VERSION 5.7 ;
  NOWIREEXTENSIONATPIN ON ;
  DIVIDERCHAR "/" ;
  BUSBITCHARS "[]" ;
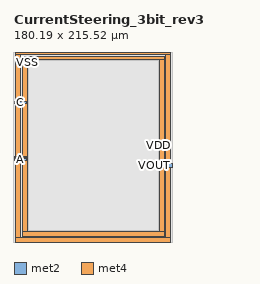
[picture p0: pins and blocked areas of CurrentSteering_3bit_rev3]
MACRO CurrentSteering_3bit_rev3
  CLASS BLOCK ;
  FOREIGN CurrentSteering_3bit_rev3 ;
  ORIGIN -36.730 137.180 ;
  SIZE 180.190 BY 215.520 ;
  PIN A
    USE SIGNAL ;
    ANTENNAGATEAREA 400.000000 ;
    PORT
      LAYER met2 ;
        RECT 36.820 -44.680 51 -42.990 ;
    END
  END A
  PIN B
    USE SIGNAL ;
    ANTENNAGATEAREA 800.000000 ;
    PORT
      LAYER met2 ;
        RECT 36.820 -41.470 51 -39.780 ;
    END
  END B
  PIN C
    USE SIGNAL ;
    ANTENNAGATEAREA 1600.000000 ;
    PORT
      LAYER met2 ;
        RECT 36.730 19.740 51 22.090 ;
    END
  END C
  PIN VOUT
    USE SIGNAL ;
    ANTENNADIFFAREA 974.399963 ;
    PORT
      LAYER met2 ;
        RECT 201 -52.320 216.920 -48.480 ;
    END
  END VOUT
  PIN VDD
    USE POWER ;
    ANTENNADIFFAREA 106.574997 ;
    PORT
      LAYER met4 ;
        RECT 46.210 69.710 207.460 73.770 ;
        RECT 46.210 -125.470 51.900 69.710 ;
        RECT 201.240 -125.470 207.460 69.710 ;
        RECT 46.210 -130.890 207.460 -125.470 ;
    END
  END VDD
  PIN VSS
    USE GROUND ;
    ANTENNADIFFAREA 33.846699 ;
    PORT
      LAYER met4 ;
        RECT 38.770 75.200 214.730 78.340 ;
        RECT 38.770 -132.380 44.620 75.200 ;
        RECT 208.880 -132.380 214.730 75.200 ;
        RECT 38.770 -137.180 214.730 -132.380 ;
    END
  END VSS
  OBS
      LAYER pwell ;
        RECT 53 -124 201 69 ;
        RECT 36.19 -137.52 216 78 ;

        RECT 85.340 16.310 95.230 58.890 ;
        RECT 103.570 16.150 113.460 58.730 ;
        RECT 121.970 16.100 131.860 58.680 ;
        RECT 140.740 16.250 150.630 58.830 ;
        RECT 59.530 -47.920 69.420 -5.340 ;
        RECT 76.580 -47.920 86.470 -5.340 ;
        RECT 102.420 -47.940 112.310 -5.360 ;
        RECT 123.440 -47.940 133.330 -5.360 ;
        RECT 147.510 -47.970 157.400 -5.390 ;
        RECT 165.580 -47.970 175.470 -5.390 ;
        RECT 88.620 -115.630 98.510 -73.050 ;
        RECT 105.010 -115.630 114.900 -73.050 ;
        RECT 120.970 -115.630 130.860 -73.050 ;
        RECT 137.960 -115.630 147.850 -73.050 ;
      LAYER li1 ;
        RECT 53 -124 201 69 ;
        RECT 36.19 -137.52 216 78 ;

        RECT 62.245 60.815 62.415 62.815 ;
        RECT 72.885 60.815 73.055 62.815 ;
        RECT 87.580 62.010 87.750 62.510 ;
        RECT 93.220 62.010 93.390 62.510 ;
        RECT 87.965 61.780 93.005 61.950 ;
        RECT 105.810 61.850 105.980 62.350 ;
        RECT 111.450 61.850 111.620 62.350 ;
        RECT 124.210 61.800 124.380 62.300 ;
        RECT 129.850 61.800 130.020 62.300 ;
        RECT 142.980 61.950 143.150 62.450 ;
        RECT 148.620 61.950 148.790 62.450 ;
        RECT 106.195 61.620 111.235 61.790 ;
        RECT 124.595 61.570 129.635 61.740 ;
        RECT 143.365 61.720 148.405 61.890 ;
        RECT 62.630 60.585 72.670 60.755 ;
        RECT 85.580 58.480 94.990 58.650 ;
        RECT 64.730 54.890 70.460 57.050 ;
        RECT 85.580 16.720 85.750 58.480 ;
        RECT 87.040 17.580 87.210 57.620 ;
        RECT 88.620 17.580 88.790 57.620 ;
        RECT 90.200 17.580 90.370 57.620 ;
        RECT 91.780 17.580 91.950 57.620 ;
        RECT 93.360 17.580 93.530 57.620 ;
        RECT 94.820 16.720 94.990 58.480 ;
        RECT 85.580 16.550 94.990 16.720 ;
        RECT 103.810 58.320 113.220 58.490 ;
        RECT 103.810 16.560 103.980 58.320 ;
        RECT 105.270 17.420 105.440 57.460 ;
        RECT 106.850 17.420 107.020 57.460 ;
        RECT 108.430 17.420 108.600 57.460 ;
        RECT 110.010 17.420 110.180 57.460 ;
        RECT 111.590 17.420 111.760 57.460 ;
        RECT 113.050 16.560 113.220 58.320 ;
        RECT 103.810 16.390 113.220 16.560 ;
        RECT 122.210 58.270 131.620 58.440 ;
        RECT 122.210 16.510 122.380 58.270 ;
        RECT 123.670 17.370 123.840 57.410 ;
        RECT 125.250 17.370 125.420 57.410 ;
        RECT 126.830 17.370 127.000 57.410 ;
        RECT 128.410 17.370 128.580 57.410 ;
        RECT 129.990 17.370 130.160 57.410 ;
        RECT 131.450 16.510 131.620 58.270 ;
        RECT 122.210 16.340 131.620 16.510 ;
        RECT 140.980 58.420 150.390 58.590 ;
        RECT 140.980 16.660 141.150 58.420 ;
        RECT 142.440 17.520 142.610 57.560 ;
        RECT 144.020 17.520 144.190 57.560 ;
        RECT 145.600 17.520 145.770 57.560 ;
        RECT 147.180 17.520 147.350 57.560 ;
        RECT 148.760 17.520 148.930 57.560 ;
        RECT 150.220 16.660 150.390 58.420 ;
        RECT 140.980 16.490 150.390 16.660 ;
        RECT 178.060 6.990 182.050 31.190 ;
        RECT 61.770 -2.220 61.940 -1.720 ;
        RECT 67.410 -2.220 67.580 -1.720 ;
        RECT 78.820 -2.220 78.990 -1.720 ;
        RECT 84.460 -2.220 84.630 -1.720 ;
        RECT 104.660 -2.240 104.830 -1.740 ;
        RECT 110.300 -2.240 110.470 -1.740 ;
        RECT 125.680 -2.240 125.850 -1.740 ;
        RECT 131.320 -2.240 131.490 -1.740 ;
        RECT 149.750 -2.270 149.920 -1.770 ;
        RECT 155.390 -2.270 155.560 -1.770 ;
        RECT 167.820 -2.270 167.990 -1.770 ;
        RECT 173.460 -2.270 173.630 -1.770 ;
        RECT 62.155 -2.450 67.195 -2.280 ;
        RECT 79.205 -2.450 84.245 -2.280 ;
        RECT 105.045 -2.470 110.085 -2.300 ;
        RECT 126.065 -2.470 131.105 -2.300 ;
        RECT 150.135 -2.500 155.175 -2.330 ;
        RECT 168.205 -2.500 173.245 -2.330 ;
        RECT 59.770 -5.750 69.180 -5.580 ;
        RECT 59.770 -47.510 59.940 -5.750 ;
        RECT 61.230 -46.650 61.400 -6.610 ;
        RECT 62.810 -46.650 62.980 -6.610 ;
        RECT 64.390 -46.650 64.560 -6.610 ;
        RECT 65.970 -46.650 66.140 -6.610 ;
        RECT 67.550 -46.650 67.720 -6.610 ;
        RECT 69.010 -47.510 69.180 -5.750 ;
        RECT 59.770 -47.680 69.180 -47.510 ;
        RECT 76.820 -5.750 86.230 -5.580 ;
        RECT 76.820 -47.510 76.990 -5.750 ;
        RECT 78.280 -46.650 78.450 -6.610 ;
        RECT 79.860 -46.650 80.030 -6.610 ;
        RECT 81.440 -46.650 81.610 -6.610 ;
        RECT 83.020 -46.650 83.190 -6.610 ;
        RECT 84.600 -46.650 84.770 -6.610 ;
        RECT 86.060 -47.510 86.230 -5.750 ;
        RECT 76.820 -47.680 86.230 -47.510 ;
        RECT 102.660 -5.770 112.070 -5.600 ;
        RECT 102.660 -47.530 102.830 -5.770 ;
        RECT 104.120 -46.670 104.290 -6.630 ;
        RECT 105.700 -46.670 105.870 -6.630 ;
        RECT 107.280 -46.670 107.450 -6.630 ;
        RECT 108.860 -46.670 109.030 -6.630 ;
        RECT 110.440 -46.670 110.610 -6.630 ;
        RECT 111.900 -47.530 112.070 -5.770 ;
        RECT 102.660 -47.700 112.070 -47.530 ;
        RECT 123.680 -5.770 133.090 -5.600 ;
        RECT 123.680 -47.530 123.850 -5.770 ;
        RECT 125.140 -46.670 125.310 -6.630 ;
        RECT 126.720 -46.670 126.890 -6.630 ;
        RECT 128.300 -46.670 128.470 -6.630 ;
        RECT 129.880 -46.670 130.050 -6.630 ;
        RECT 131.460 -46.670 131.630 -6.630 ;
        RECT 132.920 -47.530 133.090 -5.770 ;
        RECT 123.680 -47.700 133.090 -47.530 ;
        RECT 147.750 -5.800 157.160 -5.630 ;
        RECT 147.750 -47.560 147.920 -5.800 ;
        RECT 149.210 -46.700 149.380 -6.660 ;
        RECT 150.790 -46.700 150.960 -6.660 ;
        RECT 152.370 -46.700 152.540 -6.660 ;
        RECT 153.950 -46.700 154.120 -6.660 ;
        RECT 155.530 -46.700 155.700 -6.660 ;
        RECT 156.990 -47.560 157.160 -5.800 ;
        RECT 147.750 -47.730 157.160 -47.560 ;
        RECT 165.820 -5.800 175.230 -5.630 ;
        RECT 165.820 -47.560 165.990 -5.800 ;
        RECT 167.280 -46.700 167.450 -6.660 ;
        RECT 168.860 -46.700 169.030 -6.660 ;
        RECT 170.440 -46.700 170.610 -6.660 ;
        RECT 172.020 -46.700 172.190 -6.660 ;
        RECT 173.600 -46.700 173.770 -6.660 ;
        RECT 175.060 -47.560 175.230 -5.800 ;
        RECT 165.820 -47.730 175.230 -47.560 ;
        RECT 178.070 -57.480 182.020 -43.300 ;
        RECT 90.860 -69.930 91.030 -69.430 ;
        RECT 96.500 -69.930 96.670 -69.430 ;
        RECT 107.250 -69.930 107.420 -69.430 ;
        RECT 112.890 -69.930 113.060 -69.430 ;
        RECT 123.210 -69.930 123.380 -69.430 ;
        RECT 128.850 -69.930 129.020 -69.430 ;
        RECT 140.200 -69.930 140.370 -69.430 ;
        RECT 145.840 -69.930 146.010 -69.430 ;
        RECT 91.245 -70.160 96.285 -69.990 ;
        RECT 107.635 -70.160 112.675 -69.990 ;
        RECT 123.595 -70.160 128.635 -69.990 ;
        RECT 140.585 -70.160 145.625 -69.990 ;
        RECT 88.860 -73.460 98.270 -73.290 ;
        RECT 88.860 -115.220 89.030 -73.460 ;
        RECT 90.320 -114.360 90.490 -74.320 ;
        RECT 91.900 -114.360 92.070 -74.320 ;
        RECT 93.480 -114.360 93.650 -74.320 ;
        RECT 95.060 -114.360 95.230 -74.320 ;
        RECT 96.640 -114.360 96.810 -74.320 ;
        RECT 98.100 -115.220 98.270 -73.460 ;
        RECT 88.860 -115.390 98.270 -115.220 ;
        RECT 105.250 -73.460 114.660 -73.290 ;
        RECT 105.250 -115.220 105.420 -73.460 ;
        RECT 106.710 -114.360 106.880 -74.320 ;
        RECT 108.290 -114.360 108.460 -74.320 ;
        RECT 109.870 -114.360 110.040 -74.320 ;
        RECT 111.450 -114.360 111.620 -74.320 ;
        RECT 113.030 -114.360 113.200 -74.320 ;
        RECT 114.490 -115.220 114.660 -73.460 ;
        RECT 105.250 -115.390 114.660 -115.220 ;
        RECT 121.210 -73.460 130.620 -73.290 ;
        RECT 121.210 -115.220 121.380 -73.460 ;
        RECT 122.670 -114.360 122.840 -74.320 ;
        RECT 124.250 -114.360 124.420 -74.320 ;
        RECT 125.830 -114.360 126.000 -74.320 ;
        RECT 127.410 -114.360 127.580 -74.320 ;
        RECT 128.990 -114.360 129.160 -74.320 ;
        RECT 130.450 -115.220 130.620 -73.460 ;
        RECT 121.210 -115.390 130.620 -115.220 ;
        RECT 138.200 -73.460 147.610 -73.290 ;
        RECT 138.200 -115.220 138.370 -73.460 ;
        RECT 139.660 -114.360 139.830 -74.320 ;
        RECT 141.240 -114.360 141.410 -74.320 ;
        RECT 142.820 -114.360 142.990 -74.320 ;
        RECT 144.400 -114.360 144.570 -74.320 ;
        RECT 145.980 -114.360 146.150 -74.320 ;
        RECT 147.440 -115.220 147.610 -73.460 ;
        RECT 138.200 -115.390 147.610 -115.220 ;
      LAYER mcon ;
        RECT 53 -124 201 69 ;
        RECT 36.19 -137.52 216 78 ;

        RECT 62.245 60.895 62.415 62.735 ;
        RECT 72.885 60.895 73.055 62.735 ;
        RECT 87.580 62.090 87.750 62.430 ;
        RECT 93.220 62.090 93.390 62.430 ;
        RECT 88.045 61.780 92.925 61.950 ;
        RECT 105.810 61.930 105.980 62.270 ;
        RECT 111.450 61.930 111.620 62.270 ;
        RECT 124.210 61.880 124.380 62.220 ;
        RECT 129.850 61.880 130.020 62.220 ;
        RECT 142.980 62.030 143.150 62.370 ;
        RECT 148.620 62.030 148.790 62.370 ;
        RECT 106.275 61.620 111.155 61.790 ;
        RECT 124.675 61.570 129.555 61.740 ;
        RECT 143.445 61.720 148.325 61.890 ;
        RECT 62.710 60.585 72.590 60.755 ;
        RECT 64.810 54.975 70.380 56.960 ;
        RECT 87.040 17.660 87.210 57.540 ;
        RECT 88.620 17.660 88.790 57.540 ;
        RECT 90.200 17.660 90.370 57.540 ;
        RECT 91.780 17.660 91.950 57.540 ;
        RECT 93.360 17.660 93.530 57.540 ;
        RECT 105.270 17.500 105.440 57.380 ;
        RECT 106.850 17.500 107.020 57.380 ;
        RECT 108.430 17.500 108.600 57.380 ;
        RECT 110.010 17.500 110.180 57.380 ;
        RECT 111.590 17.500 111.760 57.380 ;
        RECT 123.670 17.450 123.840 57.330 ;
        RECT 125.250 17.450 125.420 57.330 ;
        RECT 126.830 17.450 127.000 57.330 ;
        RECT 128.410 17.450 128.580 57.330 ;
        RECT 129.990 17.450 130.160 57.330 ;
        RECT 142.440 17.600 142.610 57.480 ;
        RECT 144.020 17.600 144.190 57.480 ;
        RECT 145.600 17.600 145.770 57.480 ;
        RECT 147.180 17.600 147.350 57.480 ;
        RECT 148.760 17.600 148.930 57.480 ;
        RECT 178.250 29.440 179.870 30.110 ;
        RECT 180.290 29.390 181.910 30.060 ;
        RECT 178.230 28.400 179.850 29.070 ;
        RECT 180.270 28.440 181.890 29.110 ;
        RECT 178.230 27.530 179.850 28.200 ;
        RECT 180.260 27.530 181.880 28.200 ;
        RECT 178.220 26.610 179.840 27.280 ;
        RECT 180.260 26.630 181.880 27.300 ;
        RECT 178.280 17.820 179.330 18.570 ;
        RECT 180.530 17.870 181.580 18.620 ;
        RECT 178.210 9.810 179.830 10.480 ;
        RECT 180.310 9.830 181.930 10.500 ;
        RECT 178.200 8.940 179.820 9.610 ;
        RECT 180.340 8.940 181.960 9.610 ;
        RECT 178.210 8.010 179.830 8.680 ;
        RECT 180.350 8.020 181.970 8.690 ;
        RECT 61.770 -2.140 61.940 -1.800 ;
        RECT 67.410 -2.140 67.580 -1.800 ;
        RECT 78.820 -2.140 78.990 -1.800 ;
        RECT 84.460 -2.140 84.630 -1.800 ;
        RECT 104.660 -2.160 104.830 -1.820 ;
        RECT 110.300 -2.160 110.470 -1.820 ;
        RECT 125.680 -2.160 125.850 -1.820 ;
        RECT 131.320 -2.160 131.490 -1.820 ;
        RECT 149.750 -2.190 149.920 -1.850 ;
        RECT 155.390 -2.190 155.560 -1.850 ;
        RECT 167.820 -2.190 167.990 -1.850 ;
        RECT 173.460 -2.190 173.630 -1.850 ;
        RECT 62.235 -2.450 67.115 -2.280 ;
        RECT 79.285 -2.450 84.165 -2.280 ;
        RECT 105.125 -2.470 110.005 -2.300 ;
        RECT 126.145 -2.470 131.025 -2.300 ;
        RECT 150.215 -2.500 155.095 -2.330 ;
        RECT 168.285 -2.500 173.165 -2.330 ;
        RECT 61.230 -46.570 61.400 -6.690 ;
        RECT 62.810 -46.570 62.980 -6.690 ;
        RECT 64.390 -46.570 64.560 -6.690 ;
        RECT 65.970 -46.570 66.140 -6.690 ;
        RECT 67.550 -46.570 67.720 -6.690 ;
        RECT 78.280 -46.570 78.450 -6.690 ;
        RECT 79.860 -46.570 80.030 -6.690 ;
        RECT 81.440 -46.570 81.610 -6.690 ;
        RECT 83.020 -46.570 83.190 -6.690 ;
        RECT 84.600 -46.570 84.770 -6.690 ;
        RECT 104.120 -46.590 104.290 -6.710 ;
        RECT 105.700 -46.590 105.870 -6.710 ;
        RECT 107.280 -46.590 107.450 -6.710 ;
        RECT 108.860 -46.590 109.030 -6.710 ;
        RECT 110.440 -46.590 110.610 -6.710 ;
        RECT 125.140 -46.590 125.310 -6.710 ;
        RECT 126.720 -46.590 126.890 -6.710 ;
        RECT 128.300 -46.590 128.470 -6.710 ;
        RECT 129.880 -46.590 130.050 -6.710 ;
        RECT 131.460 -46.590 131.630 -6.710 ;
        RECT 149.210 -46.620 149.380 -6.740 ;
        RECT 150.790 -46.620 150.960 -6.740 ;
        RECT 152.370 -46.620 152.540 -6.740 ;
        RECT 153.950 -46.620 154.120 -6.740 ;
        RECT 155.530 -46.620 155.700 -6.740 ;
        RECT 167.280 -46.620 167.450 -6.740 ;
        RECT 168.860 -46.620 169.030 -6.740 ;
        RECT 170.440 -46.620 170.610 -6.740 ;
        RECT 172.020 -46.620 172.190 -6.740 ;
        RECT 173.600 -46.620 173.770 -6.740 ;
        RECT 178.560 -44.520 179.450 -43.780 ;
        RECT 180.460 -44.540 181.350 -43.800 ;
        RECT 178.520 -46.010 179.410 -45.270 ;
        RECT 180.450 -46.000 181.340 -45.260 ;
        RECT 178.470 -54.760 179.360 -54.020 ;
        RECT 180.670 -54.720 181.560 -53.980 ;
        RECT 178.420 -57.190 179.310 -56.450 ;
        RECT 180.670 -57.170 181.560 -56.430 ;
        RECT 90.860 -69.850 91.030 -69.510 ;
        RECT 96.500 -69.850 96.670 -69.510 ;
        RECT 107.250 -69.850 107.420 -69.510 ;
        RECT 112.890 -69.850 113.060 -69.510 ;
        RECT 123.210 -69.850 123.380 -69.510 ;
        RECT 128.850 -69.850 129.020 -69.510 ;
        RECT 140.200 -69.850 140.370 -69.510 ;
        RECT 145.840 -69.850 146.010 -69.510 ;
        RECT 91.325 -70.160 96.205 -69.990 ;
        RECT 107.715 -70.160 112.595 -69.990 ;
        RECT 123.675 -70.160 128.555 -69.990 ;
        RECT 140.665 -70.160 145.545 -69.990 ;
        RECT 90.320 -114.280 90.490 -74.400 ;
        RECT 91.900 -114.280 92.070 -74.400 ;
        RECT 93.480 -114.280 93.650 -74.400 ;
        RECT 95.060 -114.280 95.230 -74.400 ;
        RECT 96.640 -114.280 96.810 -74.400 ;
        RECT 106.710 -114.280 106.880 -74.400 ;
        RECT 108.290 -114.280 108.460 -74.400 ;
        RECT 109.870 -114.280 110.040 -74.400 ;
        RECT 111.450 -114.280 111.620 -74.400 ;
        RECT 113.030 -114.280 113.200 -74.400 ;
        RECT 122.670 -114.280 122.840 -74.400 ;
        RECT 124.250 -114.280 124.420 -74.400 ;
        RECT 125.830 -114.280 126.000 -74.400 ;
        RECT 127.410 -114.280 127.580 -74.400 ;
        RECT 128.990 -114.280 129.160 -74.400 ;
        RECT 139.660 -114.280 139.830 -74.400 ;
        RECT 141.240 -114.280 141.410 -74.400 ;
        RECT 142.820 -114.280 142.990 -74.400 ;
        RECT 144.400 -114.280 144.570 -74.400 ;
        RECT 145.980 -114.280 146.150 -74.400 ;
      LAYER met1 ;
        RECT 53 -124 201 69 ;
        RECT 36.19 -137.52 216 78 ;

        RECT 82.560 62.820 86.190 62.900 ;
        RECT 77.710 62.810 86.190 62.820 ;
        RECT 62.215 62.180 62.445 62.795 ;
        RECT 72.810 62.490 86.190 62.810 ;
        RECT 72.810 62.180 87.790 62.490 ;
        RECT 62.215 62.030 87.790 62.180 ;
        RECT 93.190 62.030 93.420 62.490 ;
        RECT 100.790 62.330 104.420 62.740 ;
        RECT 62.215 61.580 86.190 62.030 ;
        RECT 88.190 61.980 92.680 62.010 ;
        RECT 87.985 61.750 92.985 61.980 ;
        RECT 100.790 61.870 106.020 62.330 ;
        RECT 111.420 61.870 111.650 62.330 ;
        RECT 119.190 62.280 122.820 62.690 ;
        RECT 137.960 62.430 141.590 62.840 ;
        RECT 62.215 61.490 84.150 61.580 ;
        RECT 62.215 60.835 62.445 61.490 ;
        RECT 72.810 60.820 84.150 61.490 ;
        RECT 75.050 60.810 84.150 60.820 ;
        RECT 63.080 60.785 72.100 60.790 ;
        RECT 62.650 60.555 72.650 60.785 ;
        RECT 63.080 60.350 72.100 60.555 ;
        RECT 64.730 59.860 72.100 60.350 ;
        RECT 64.730 59.690 72.120 59.860 ;
        RECT 75.050 59.690 83.190 60.810 ;
        RECT 64.730 57.970 83.190 59.690 ;
        RECT 88.190 59.340 92.680 61.750 ;
        RECT 100.790 61.420 104.420 61.870 ;
        RECT 106.420 61.820 110.910 61.850 ;
        RECT 119.190 61.820 124.420 62.280 ;
        RECT 129.820 61.820 130.050 62.280 ;
        RECT 137.960 61.970 143.190 62.430 ;
        RECT 148.590 61.970 148.820 62.430 ;
        RECT 106.215 61.590 111.215 61.820 ;
        RECT 64.730 56.520 70.480 57.970 ;
        RECT 64.750 54.945 70.440 56.520 ;
        RECT 77.840 53.390 83.190 57.970 ;
        RECT 87.010 57.130 87.240 57.600 ;
        RECT 86.900 56.530 87.330 57.130 ;
        RECT 88.590 57.090 88.820 57.600 ;
        RECT 90.170 57.090 90.400 57.600 ;
        RECT 88.530 56.590 88.960 57.090 ;
        RECT 90.050 56.590 90.480 57.090 ;
        RECT 91.750 57.080 91.980 57.600 ;
        RECT 93.330 57.080 93.560 57.600 ;
        RECT 87.010 17.600 87.240 56.530 ;
        RECT 88.590 17.600 88.820 56.590 ;
        RECT 90.170 17.600 90.400 56.590 ;
        RECT 91.640 56.580 92.070 57.080 ;
        RECT 93.180 56.580 93.610 57.080 ;
        RECT 91.750 17.600 91.980 56.580 ;
        RECT 93.330 17.600 93.560 56.580 ;
        RECT 100.810 54.170 102.610 61.420 ;
        RECT 106.420 59.180 110.910 61.590 ;
        RECT 119.190 61.370 122.820 61.820 ;
        RECT 124.820 61.770 129.310 61.800 ;
        RECT 124.615 61.540 129.615 61.770 ;
        RECT 105.240 56.970 105.470 57.440 ;
        RECT 105.130 56.370 105.560 56.970 ;
        RECT 106.820 56.930 107.050 57.440 ;
        RECT 108.400 56.930 108.630 57.440 ;
        RECT 106.760 56.430 107.190 56.930 ;
        RECT 108.280 56.430 108.710 56.930 ;
        RECT 109.980 56.920 110.210 57.440 ;
        RECT 111.560 56.920 111.790 57.440 ;
        RECT 105.240 17.440 105.470 56.370 ;
        RECT 106.820 17.440 107.050 56.430 ;
        RECT 108.400 17.440 108.630 56.430 ;
        RECT 109.870 56.420 110.300 56.920 ;
        RECT 111.410 56.420 111.840 56.920 ;
        RECT 109.980 17.440 110.210 56.420 ;
        RECT 111.560 17.440 111.790 56.420 ;
        RECT 119.220 54.100 121.330 61.370 ;
        RECT 124.820 59.130 129.310 61.540 ;
        RECT 137.960 61.520 141.590 61.970 ;
        RECT 143.590 61.920 148.080 61.950 ;
        RECT 143.385 61.690 148.385 61.920 ;
        RECT 123.640 56.920 123.870 57.390 ;
        RECT 123.530 56.320 123.960 56.920 ;
        RECT 125.220 56.880 125.450 57.390 ;
        RECT 126.800 56.880 127.030 57.390 ;
        RECT 125.160 56.380 125.590 56.880 ;
        RECT 126.680 56.380 127.110 56.880 ;
        RECT 128.380 56.870 128.610 57.390 ;
        RECT 129.960 56.870 130.190 57.390 ;
        RECT 123.640 17.390 123.870 56.320 ;
        RECT 125.220 17.390 125.450 56.380 ;
        RECT 126.800 17.390 127.030 56.380 ;
        RECT 128.270 56.370 128.700 56.870 ;
        RECT 129.810 56.370 130.240 56.870 ;
        RECT 128.380 17.390 128.610 56.370 ;
        RECT 129.960 17.390 130.190 56.370 ;
        RECT 138.030 54.190 140.140 61.520 ;
        RECT 143.590 59.280 148.080 61.690 ;
        RECT 142.410 57.070 142.640 57.540 ;
        RECT 142.300 56.470 142.730 57.070 ;
        RECT 143.990 57.030 144.220 57.540 ;
        RECT 145.570 57.030 145.800 57.540 ;
        RECT 143.930 56.530 144.360 57.030 ;
        RECT 145.450 56.530 145.880 57.030 ;
        RECT 147.150 57.020 147.380 57.540 ;
        RECT 148.730 57.020 148.960 57.540 ;
        RECT 142.410 17.540 142.640 56.470 ;
        RECT 143.990 17.540 144.220 56.530 ;
        RECT 145.570 17.540 145.800 56.530 ;
        RECT 147.040 56.520 147.470 57.020 ;
        RECT 148.580 56.520 149.010 57.020 ;
        RECT 147.150 17.540 147.380 56.520 ;
        RECT 148.730 17.540 148.960 56.520 ;
        RECT 178.060 17.220 182.050 31.190 ;
        RECT 178.060 6.990 182.050 10.620 ;
        RECT 56.750 -1.740 60.380 -1.330 ;
        RECT 73.800 -1.740 77.430 -1.330 ;
        RECT 56.750 -2.200 61.980 -1.740 ;
        RECT 67.380 -2.200 67.610 -1.740 ;
        RECT 73.800 -2.200 79.030 -1.740 ;
        RECT 84.430 -2.200 84.660 -1.740 ;
        RECT 99.640 -1.760 103.270 -1.350 ;
        RECT 120.660 -1.760 124.290 -1.350 ;
        RECT 56.750 -2.650 60.380 -2.200 ;
        RECT 62.380 -2.250 66.870 -2.220 ;
        RECT 62.175 -2.480 67.175 -2.250 ;
        RECT 56.920 -11.860 58.960 -2.650 ;
        RECT 62.380 -4.890 66.870 -2.480 ;
        RECT 73.800 -2.650 77.430 -2.200 ;
        RECT 99.640 -2.220 104.870 -1.760 ;
        RECT 110.270 -2.220 110.500 -1.760 ;
        RECT 120.660 -2.220 125.890 -1.760 ;
        RECT 131.290 -2.220 131.520 -1.760 ;
        RECT 144.730 -1.790 148.360 -1.380 ;
        RECT 162.800 -1.790 166.430 -1.380 ;
        RECT 79.430 -2.250 83.920 -2.220 ;
        RECT 79.225 -2.480 84.225 -2.250 ;
        RECT 61.200 -7.100 61.430 -6.630 ;
        RECT 61.090 -7.700 61.520 -7.100 ;
        RECT 62.780 -7.140 63.010 -6.630 ;
        RECT 64.360 -7.140 64.590 -6.630 ;
        RECT 62.720 -7.640 63.150 -7.140 ;
        RECT 64.240 -7.640 64.670 -7.140 ;
        RECT 65.940 -7.150 66.170 -6.630 ;
        RECT 67.520 -7.150 67.750 -6.630 ;
        RECT 61.200 -46.630 61.430 -7.700 ;
        RECT 62.780 -46.630 63.010 -7.640 ;
        RECT 64.360 -46.630 64.590 -7.640 ;
        RECT 65.830 -7.650 66.260 -7.150 ;
        RECT 67.370 -7.650 67.800 -7.150 ;
        RECT 65.940 -46.630 66.170 -7.650 ;
        RECT 67.520 -46.630 67.750 -7.650 ;
        RECT 73.890 -11.940 75.930 -2.650 ;
        RECT 79.430 -4.890 83.920 -2.480 ;
        RECT 99.640 -2.670 103.270 -2.220 ;
        RECT 105.270 -2.270 109.760 -2.240 ;
        RECT 105.065 -2.500 110.065 -2.270 ;
        RECT 78.250 -7.100 78.480 -6.630 ;
        RECT 78.140 -7.700 78.570 -7.100 ;
        RECT 79.830 -7.140 80.060 -6.630 ;
        RECT 81.410 -7.140 81.640 -6.630 ;
        RECT 79.770 -7.640 80.200 -7.140 ;
        RECT 81.290 -7.640 81.720 -7.140 ;
        RECT 82.990 -7.150 83.220 -6.630 ;
        RECT 84.570 -7.150 84.800 -6.630 ;
        RECT 78.250 -46.630 78.480 -7.700 ;
        RECT 79.830 -46.630 80.060 -7.640 ;
        RECT 81.410 -46.630 81.640 -7.640 ;
        RECT 82.880 -7.650 83.310 -7.150 ;
        RECT 84.420 -7.650 84.850 -7.150 ;
        RECT 82.990 -46.630 83.220 -7.650 ;
        RECT 84.570 -46.630 84.800 -7.650 ;
        RECT 99.660 -11.900 101.700 -2.670 ;
        RECT 105.270 -4.910 109.760 -2.500 ;
        RECT 120.660 -2.670 124.290 -2.220 ;
        RECT 126.290 -2.270 130.780 -2.240 ;
        RECT 144.730 -2.250 149.960 -1.790 ;
        RECT 155.360 -2.250 155.590 -1.790 ;
        RECT 162.800 -2.250 168.030 -1.790 ;
        RECT 173.430 -2.250 173.660 -1.790 ;
        RECT 126.085 -2.500 131.085 -2.270 ;
        RECT 104.090 -7.120 104.320 -6.650 ;
        RECT 103.980 -7.720 104.410 -7.120 ;
        RECT 105.670 -7.160 105.900 -6.650 ;
        RECT 107.250 -7.160 107.480 -6.650 ;
        RECT 105.610 -7.660 106.040 -7.160 ;
        RECT 107.130 -7.660 107.560 -7.160 ;
        RECT 108.830 -7.170 109.060 -6.650 ;
        RECT 110.410 -7.170 110.640 -6.650 ;
        RECT 104.090 -46.650 104.320 -7.720 ;
        RECT 105.670 -46.650 105.900 -7.660 ;
        RECT 107.250 -46.650 107.480 -7.660 ;
        RECT 108.720 -7.670 109.150 -7.170 ;
        RECT 110.260 -7.670 110.690 -7.170 ;
        RECT 108.830 -46.650 109.060 -7.670 ;
        RECT 110.410 -46.650 110.640 -7.670 ;
        RECT 120.800 -11.810 122.840 -2.670 ;
        RECT 126.290 -4.910 130.780 -2.500 ;
        RECT 144.730 -2.700 148.360 -2.250 ;
        RECT 150.360 -2.300 154.850 -2.270 ;
        RECT 150.155 -2.530 155.155 -2.300 ;
        RECT 125.110 -7.120 125.340 -6.650 ;
        RECT 125.000 -7.720 125.430 -7.120 ;
        RECT 126.690 -7.160 126.920 -6.650 ;
        RECT 128.270 -7.160 128.500 -6.650 ;
        RECT 126.630 -7.660 127.060 -7.160 ;
        RECT 128.150 -7.660 128.580 -7.160 ;
        RECT 129.850 -7.170 130.080 -6.650 ;
        RECT 131.430 -7.170 131.660 -6.650 ;
        RECT 125.110 -46.650 125.340 -7.720 ;
        RECT 126.690 -46.650 126.920 -7.660 ;
        RECT 128.270 -46.650 128.500 -7.660 ;
        RECT 129.740 -7.670 130.170 -7.170 ;
        RECT 131.280 -7.670 131.710 -7.170 ;
        RECT 129.850 -46.650 130.080 -7.670 ;
        RECT 131.430 -46.650 131.660 -7.670 ;
        RECT 144.760 -11.880 146.800 -2.700 ;
        RECT 150.360 -4.940 154.850 -2.530 ;
        RECT 162.800 -2.700 166.430 -2.250 ;
        RECT 168.430 -2.300 172.920 -2.270 ;
        RECT 168.225 -2.530 173.225 -2.300 ;
        RECT 149.180 -7.150 149.410 -6.680 ;
        RECT 149.070 -7.750 149.500 -7.150 ;
        RECT 150.760 -7.190 150.990 -6.680 ;
        RECT 152.340 -7.190 152.570 -6.680 ;
        RECT 150.700 -7.690 151.130 -7.190 ;
        RECT 152.220 -7.690 152.650 -7.190 ;
        RECT 153.920 -7.200 154.150 -6.680 ;
        RECT 155.500 -7.200 155.730 -6.680 ;
        RECT 149.180 -46.680 149.410 -7.750 ;
        RECT 150.760 -46.680 150.990 -7.690 ;
        RECT 152.340 -46.680 152.570 -7.690 ;
        RECT 153.810 -7.700 154.240 -7.200 ;
        RECT 155.350 -7.700 155.780 -7.200 ;
        RECT 153.920 -46.680 154.150 -7.700 ;
        RECT 155.500 -46.680 155.730 -7.700 ;
        RECT 162.890 -11.860 164.930 -2.700 ;
        RECT 168.430 -4.940 172.920 -2.530 ;
        RECT 167.250 -7.150 167.480 -6.680 ;
        RECT 167.140 -7.750 167.570 -7.150 ;
        RECT 168.830 -7.190 169.060 -6.680 ;
        RECT 170.410 -7.190 170.640 -6.680 ;
        RECT 168.770 -7.690 169.200 -7.190 ;
        RECT 170.290 -7.690 170.720 -7.190 ;
        RECT 171.990 -7.200 172.220 -6.680 ;
        RECT 173.570 -7.200 173.800 -6.680 ;
        RECT 167.250 -46.680 167.480 -7.750 ;
        RECT 168.830 -46.680 169.060 -7.690 ;
        RECT 170.410 -46.680 170.640 -7.690 ;
        RECT 171.880 -7.700 172.310 -7.200 ;
        RECT 173.420 -7.700 173.850 -7.200 ;
        RECT 171.990 -46.680 172.220 -7.700 ;
        RECT 173.570 -46.680 173.800 -7.700 ;
        RECT 178.050 -46.400 182.020 -43.350 ;
        RECT 178.070 -57.480 182.030 -53.560 ;
        RECT 135.020 -69.040 137.480 -68.840 ;
        RECT 85.840 -69.450 89.470 -69.040 ;
        RECT 102.230 -69.450 105.860 -69.040 ;
        RECT 118.190 -69.450 121.820 -69.040 ;
        RECT 135.020 -69.450 138.810 -69.040 ;
        RECT 85.840 -69.910 91.070 -69.450 ;
        RECT 96.470 -69.910 96.700 -69.450 ;
        RECT 102.230 -69.910 107.460 -69.450 ;
        RECT 112.860 -69.910 113.090 -69.450 ;
        RECT 118.190 -69.910 123.420 -69.450 ;
        RECT 128.820 -69.910 129.050 -69.450 ;
        RECT 135.020 -69.910 140.410 -69.450 ;
        RECT 145.810 -69.910 146.040 -69.450 ;
        RECT 85.840 -70.360 89.470 -69.910 ;
        RECT 91.470 -69.960 95.960 -69.930 ;
        RECT 91.265 -70.190 96.265 -69.960 ;
        RECT 85.840 -79.140 88.010 -70.360 ;
        RECT 91.470 -72.600 95.960 -70.190 ;
        RECT 102.230 -70.360 105.860 -69.910 ;
        RECT 107.860 -69.960 112.350 -69.930 ;
        RECT 107.655 -70.190 112.655 -69.960 ;
        RECT 90.290 -74.810 90.520 -74.340 ;
        RECT 90.180 -75.410 90.610 -74.810 ;
        RECT 91.870 -74.850 92.100 -74.340 ;
        RECT 93.450 -74.850 93.680 -74.340 ;
        RECT 91.810 -75.350 92.240 -74.850 ;
        RECT 93.330 -75.350 93.760 -74.850 ;
        RECT 95.030 -74.860 95.260 -74.340 ;
        RECT 96.610 -74.860 96.840 -74.340 ;
        RECT 90.290 -114.340 90.520 -75.410 ;
        RECT 91.870 -114.340 92.100 -75.350 ;
        RECT 93.450 -114.340 93.680 -75.350 ;
        RECT 94.920 -75.360 95.350 -74.860 ;
        RECT 96.460 -75.360 96.890 -74.860 ;
        RECT 95.030 -114.340 95.260 -75.360 ;
        RECT 96.610 -114.340 96.840 -75.360 ;
        RECT 102.370 -79.120 104.540 -70.360 ;
        RECT 107.860 -72.600 112.350 -70.190 ;
        RECT 118.190 -70.360 121.820 -69.910 ;
        RECT 123.820 -69.960 128.310 -69.930 ;
        RECT 123.615 -70.190 128.615 -69.960 ;
        RECT 106.680 -74.810 106.910 -74.340 ;
        RECT 106.570 -75.410 107.000 -74.810 ;
        RECT 108.260 -74.850 108.490 -74.340 ;
        RECT 109.840 -74.850 110.070 -74.340 ;
        RECT 108.200 -75.350 108.630 -74.850 ;
        RECT 109.720 -75.350 110.150 -74.850 ;
        RECT 111.420 -74.860 111.650 -74.340 ;
        RECT 113.000 -74.860 113.230 -74.340 ;
        RECT 106.680 -114.340 106.910 -75.410 ;
        RECT 108.260 -114.340 108.490 -75.350 ;
        RECT 109.840 -114.340 110.070 -75.350 ;
        RECT 111.310 -75.360 111.740 -74.860 ;
        RECT 112.850 -75.360 113.280 -74.860 ;
        RECT 111.420 -114.340 111.650 -75.360 ;
        RECT 113.000 -114.340 113.230 -75.360 ;
        RECT 118.440 -79.050 120.610 -70.360 ;
        RECT 123.820 -72.600 128.310 -70.190 ;
        RECT 135.020 -70.360 138.810 -69.910 ;
        RECT 140.810 -69.960 145.300 -69.930 ;
        RECT 140.605 -70.190 145.605 -69.960 ;
        RECT 122.640 -74.810 122.870 -74.340 ;
        RECT 122.530 -75.410 122.960 -74.810 ;
        RECT 124.220 -74.850 124.450 -74.340 ;
        RECT 125.800 -74.850 126.030 -74.340 ;
        RECT 124.160 -75.350 124.590 -74.850 ;
        RECT 125.680 -75.350 126.110 -74.850 ;
        RECT 127.380 -74.860 127.610 -74.340 ;
        RECT 128.960 -74.860 129.190 -74.340 ;
        RECT 122.640 -114.340 122.870 -75.410 ;
        RECT 124.220 -114.340 124.450 -75.350 ;
        RECT 125.800 -114.340 126.030 -75.350 ;
        RECT 127.270 -75.360 127.700 -74.860 ;
        RECT 128.810 -75.360 129.240 -74.860 ;
        RECT 127.380 -114.340 127.610 -75.360 ;
        RECT 128.960 -114.340 129.190 -75.360 ;
        RECT 135.020 -79.080 137.480 -70.360 ;
        RECT 140.810 -72.600 145.300 -70.190 ;
        RECT 139.630 -74.810 139.860 -74.340 ;
        RECT 139.520 -75.410 139.950 -74.810 ;
        RECT 141.210 -74.850 141.440 -74.340 ;
        RECT 142.790 -74.850 143.020 -74.340 ;
        RECT 141.150 -75.350 141.580 -74.850 ;
        RECT 142.670 -75.350 143.100 -74.850 ;
        RECT 144.370 -74.860 144.600 -74.340 ;
        RECT 145.950 -74.860 146.180 -74.340 ;
        RECT 139.630 -114.340 139.860 -75.410 ;
        RECT 141.210 -114.340 141.440 -75.350 ;
        RECT 142.790 -114.340 143.020 -75.350 ;
        RECT 144.260 -75.360 144.690 -74.860 ;
        RECT 145.800 -75.360 146.230 -74.860 ;
        RECT 144.370 -114.340 144.600 -75.360 ;
        RECT 145.950 -114.340 146.180 -75.360 ;
      LAYER via ;
        RECT 53 -124 201 69 ;
        RECT 36.19 -137.52 216 78 ;

        RECT 100.910 61.690 101.460 62.220 ;
        RECT 101.760 61.690 102.310 62.220 ;
        RECT 119.320 61.640 119.870 62.170 ;
        RECT 120.180 61.650 120.730 62.180 ;
        RECT 88.420 59.460 92.520 60.030 ;
        RECT 78.180 57.020 79.310 58.460 ;
        RECT 79.770 56.990 80.900 58.430 ;
        RECT 81.640 56.960 82.770 58.400 ;
        RECT 86.970 56.640 87.270 56.960 ;
        RECT 88.600 56.670 88.890 57.000 ;
        RECT 90.120 56.670 90.410 57.000 ;
        RECT 91.710 56.660 92.000 56.990 ;
        RECT 78.060 53.640 79.190 55.080 ;
        RECT 79.630 53.610 80.760 55.050 ;
        RECT 81.540 53.640 82.670 55.080 ;
        RECT 93.250 56.660 93.540 56.990 ;
        RECT 106.650 59.300 110.750 59.870 ;
        RECT 105.200 56.480 105.500 56.800 ;
        RECT 106.830 56.510 107.120 56.840 ;
        RECT 108.350 56.510 108.640 56.840 ;
        RECT 109.940 56.500 110.230 56.830 ;
        RECT 101.060 54.440 101.380 54.800 ;
        RECT 101.860 54.500 102.180 54.860 ;
        RECT 111.480 56.500 111.770 56.830 ;
        RECT 125.050 59.250 129.150 59.820 ;
        RECT 123.600 56.430 123.900 56.750 ;
        RECT 125.230 56.460 125.520 56.790 ;
        RECT 126.750 56.460 127.040 56.790 ;
        RECT 128.340 56.450 128.630 56.780 ;
        RECT 119.410 54.260 119.880 54.820 ;
        RECT 120.680 54.290 121.150 54.850 ;
        RECT 129.880 56.450 130.170 56.780 ;
        RECT 143.820 59.400 147.920 59.970 ;
        RECT 142.370 56.580 142.670 56.900 ;
        RECT 144.000 56.610 144.290 56.940 ;
        RECT 145.520 56.610 145.810 56.940 ;
        RECT 147.110 56.600 147.400 56.930 ;
        RECT 138.330 54.340 138.800 54.900 ;
        RECT 139.480 54.420 139.950 54.980 ;
        RECT 148.650 56.600 148.940 56.930 ;
        RECT 178.260 30.360 179.880 31.030 ;
        RECT 180.310 30.330 181.930 31.000 ;
        RECT 178.250 29.440 179.870 30.110 ;
        RECT 180.290 29.390 181.910 30.060 ;
        RECT 178.230 28.400 179.850 29.070 ;
        RECT 180.270 28.440 181.890 29.110 ;
        RECT 178.230 27.530 179.850 28.200 ;
        RECT 180.260 27.530 181.880 28.200 ;
        RECT 178.200 8.940 179.820 9.610 ;
        RECT 180.340 8.940 181.960 9.610 ;
        RECT 178.210 8.010 179.830 8.680 ;
        RECT 180.350 8.020 181.970 8.690 ;
        RECT 178.190 7.110 179.810 7.780 ;
        RECT 180.320 7.140 181.940 7.810 ;
        RECT 57.190 -2.410 57.720 -1.720 ;
        RECT 58.210 -2.350 58.740 -1.660 ;
        RECT 74.160 -2.390 74.690 -1.700 ;
        RECT 75.120 -2.310 75.650 -1.620 ;
        RECT 62.610 -4.770 66.710 -4.200 ;
        RECT 61.160 -7.590 61.460 -7.270 ;
        RECT 62.790 -7.560 63.080 -7.230 ;
        RECT 64.310 -7.560 64.600 -7.230 ;
        RECT 65.900 -7.570 66.190 -7.240 ;
        RECT 57.170 -11.540 57.700 -10.850 ;
        RECT 58.010 -11.480 58.540 -10.790 ;
        RECT 67.440 -7.570 67.730 -7.240 ;
        RECT 99.880 -2.500 100.500 -1.570 ;
        RECT 100.920 -2.480 101.540 -1.550 ;
        RECT 121.020 -2.440 121.640 -1.510 ;
        RECT 122.030 -2.410 122.650 -1.480 ;
        RECT 79.660 -4.770 83.760 -4.200 ;
        RECT 78.210 -7.590 78.510 -7.270 ;
        RECT 79.840 -7.560 80.130 -7.230 ;
        RECT 81.360 -7.560 81.650 -7.230 ;
        RECT 82.950 -7.570 83.240 -7.240 ;
        RECT 74.180 -11.520 74.710 -10.830 ;
        RECT 75.130 -11.520 75.660 -10.830 ;
        RECT 84.490 -7.570 84.780 -7.240 ;
        RECT 144.950 -2.450 145.570 -1.520 ;
        RECT 146.000 -2.440 146.620 -1.510 ;
        RECT 105.500 -4.790 109.600 -4.220 ;
        RECT 104.050 -7.610 104.350 -7.290 ;
        RECT 105.680 -7.580 105.970 -7.250 ;
        RECT 107.200 -7.580 107.490 -7.250 ;
        RECT 108.790 -7.590 109.080 -7.260 ;
        RECT 99.820 -11.560 100.440 -10.630 ;
        RECT 100.760 -11.540 101.380 -10.610 ;
        RECT 110.330 -7.590 110.620 -7.260 ;
        RECT 126.520 -4.790 130.620 -4.220 ;
        RECT 125.070 -7.610 125.370 -7.290 ;
        RECT 126.700 -7.580 126.990 -7.250 ;
        RECT 128.220 -7.580 128.510 -7.250 ;
        RECT 129.810 -7.590 130.100 -7.260 ;
        RECT 121.050 -11.500 121.670 -10.570 ;
        RECT 122.030 -11.470 122.650 -10.540 ;
        RECT 131.350 -7.590 131.640 -7.260 ;
        RECT 163.100 -2.560 163.720 -1.630 ;
        RECT 164.080 -2.540 164.740 -1.580 ;
        RECT 150.590 -4.820 154.690 -4.250 ;
        RECT 149.140 -7.640 149.440 -7.320 ;
        RECT 150.770 -7.610 151.060 -7.280 ;
        RECT 152.290 -7.610 152.580 -7.280 ;
        RECT 153.880 -7.620 154.170 -7.290 ;
        RECT 145.000 -11.500 145.620 -10.570 ;
        RECT 145.960 -11.510 146.580 -10.580 ;
        RECT 155.420 -7.620 155.710 -7.290 ;
        RECT 168.660 -4.820 172.760 -4.250 ;
        RECT 167.210 -7.640 167.510 -7.320 ;
        RECT 168.840 -7.610 169.130 -7.280 ;
        RECT 170.360 -7.610 170.650 -7.280 ;
        RECT 171.950 -7.620 172.240 -7.290 ;
        RECT 163.100 -11.530 163.720 -10.600 ;
        RECT 164.140 -11.440 164.760 -10.510 ;
        RECT 173.490 -7.620 173.780 -7.290 ;
        RECT 178.560 -44.520 179.450 -43.780 ;
        RECT 180.460 -44.540 181.350 -43.800 ;
        RECT 178.520 -46.010 179.410 -45.270 ;
        RECT 180.450 -46.000 181.340 -45.260 ;
        RECT 178.470 -54.760 179.360 -54.020 ;
        RECT 180.670 -54.720 181.560 -53.980 ;
        RECT 178.420 -57.190 179.310 -56.450 ;
        RECT 180.670 -57.170 181.560 -56.430 ;
        RECT 85.980 -70.240 86.520 -69.390 ;
        RECT 87.170 -70.160 87.710 -69.310 ;
        RECT 102.500 -70.180 103.040 -69.330 ;
        RECT 103.720 -70.180 104.260 -69.330 ;
        RECT 118.550 -70.160 119.090 -69.310 ;
        RECT 91.700 -72.480 95.800 -71.910 ;
        RECT 90.250 -75.300 90.550 -74.980 ;
        RECT 91.880 -75.270 92.170 -74.940 ;
        RECT 93.400 -75.270 93.690 -74.940 ;
        RECT 94.990 -75.280 95.280 -74.950 ;
        RECT 85.960 -78.780 86.570 -77.760 ;
        RECT 87.120 -78.740 87.730 -77.720 ;
        RECT 96.530 -75.280 96.820 -74.950 ;
        RECT 119.820 -70.200 120.360 -69.350 ;
        RECT 108.090 -72.480 112.190 -71.910 ;
        RECT 106.640 -75.300 106.940 -74.980 ;
        RECT 108.270 -75.270 108.560 -74.940 ;
        RECT 109.790 -75.270 110.080 -74.940 ;
        RECT 111.380 -75.280 111.670 -74.950 ;
        RECT 102.700 -78.280 103.240 -77.430 ;
        RECT 103.750 -78.300 104.290 -77.450 ;
        RECT 112.920 -75.280 113.210 -74.950 ;
        RECT 124.050 -72.480 128.150 -71.910 ;
        RECT 135.180 -70.410 137.350 -69.050 ;
        RECT 122.600 -75.300 122.900 -74.980 ;
        RECT 124.230 -75.270 124.520 -74.940 ;
        RECT 125.750 -75.270 126.040 -74.940 ;
        RECT 127.340 -75.280 127.630 -74.950 ;
        RECT 118.580 -78.520 119.120 -77.670 ;
        RECT 119.710 -78.540 120.250 -77.690 ;
        RECT 128.880 -75.280 129.170 -74.950 ;
        RECT 141.040 -72.480 145.140 -71.910 ;
        RECT 139.590 -75.300 139.890 -74.980 ;
        RECT 141.220 -75.270 141.510 -74.940 ;
        RECT 142.740 -75.270 143.030 -74.940 ;
        RECT 144.330 -75.280 144.620 -74.950 ;
        RECT 145.870 -75.280 146.160 -74.950 ;
      LAYER met2 ;
        RECT 53 -124 201 69 ;
        RECT 86.900 59.310 93.600 60.090 ;
        RECT 77.840 55.400 83.190 58.990 ;
        RECT 86.900 56.530 87.330 59.310 ;
        RECT 88.530 57.090 88.950 59.310 ;
        RECT 90.050 57.090 90.470 59.310 ;
        RECT 88.530 56.590 88.960 57.090 ;
        RECT 90.050 56.590 90.480 57.090 ;
        RECT 91.640 57.080 92.060 59.310 ;
        RECT 93.180 57.080 93.600 59.310 ;
        RECT 91.640 56.580 92.070 57.080 ;
        RECT 93.180 56.580 93.610 57.080 ;
        RECT 100.810 55.400 102.610 62.720 ;
        RECT 105.130 59.150 111.830 59.930 ;
        RECT 105.130 56.370 105.560 59.150 ;
        RECT 106.760 56.930 107.180 59.150 ;
        RECT 108.280 56.930 108.700 59.150 ;
        RECT 106.760 56.430 107.190 56.930 ;
        RECT 108.280 56.430 108.710 56.930 ;
        RECT 109.870 56.920 110.290 59.150 ;
        RECT 111.410 56.920 111.830 59.150 ;
        RECT 109.870 56.420 110.300 56.920 ;
        RECT 111.410 56.420 111.840 56.920 ;
        RECT 119.220 55.400 121.330 62.610 ;
        RECT 123.530 59.100 130.230 59.880 ;
        RECT 123.530 56.320 123.960 59.100 ;
        RECT 125.160 56.880 125.580 59.100 ;
        RECT 126.680 56.880 127.100 59.100 ;
        RECT 125.160 56.380 125.590 56.880 ;
        RECT 126.680 56.380 127.110 56.880 ;
        RECT 128.270 56.870 128.690 59.100 ;
        RECT 129.810 56.870 130.230 59.100 ;
        RECT 128.270 56.370 128.700 56.870 ;
        RECT 129.810 56.370 130.240 56.870 ;
        RECT 138.030 55.400 140.140 62.700 ;
        RECT 142.300 59.250 149.000 60.030 ;
        RECT 142.300 56.470 142.730 59.250 ;
        RECT 143.930 57.030 144.350 59.250 ;
        RECT 145.450 57.030 145.870 59.250 ;
        RECT 143.930 56.530 144.360 57.030 ;
        RECT 145.450 56.530 145.880 57.030 ;
        RECT 147.040 57.020 147.460 59.250 ;
        RECT 148.580 57.020 149.000 59.250 ;
        RECT 147.040 56.520 147.470 57.020 ;
        RECT 148.580 56.520 149.010 57.020 ;
        RECT 77.840 55.360 180.360 55.400 ;
        RECT 77.840 53.390 182.000 55.360 ;
        RECT 178.070 26.490 182.000 53.390 ;
        RECT 56.920 -10.040 58.960 -1.430 ;
        RECT 61.090 -4.920 67.790 -4.140 ;
        RECT 61.090 -7.700 61.520 -4.920 ;
        RECT 62.720 -7.140 63.140 -4.920 ;
        RECT 64.240 -7.140 64.660 -4.920 ;
        RECT 62.720 -7.640 63.150 -7.140 ;
        RECT 64.240 -7.640 64.670 -7.140 ;
        RECT 65.830 -7.150 66.250 -4.920 ;
        RECT 67.370 -7.150 67.790 -4.920 ;
        RECT 65.830 -7.650 66.260 -7.150 ;
        RECT 67.370 -7.650 67.800 -7.150 ;
        RECT 73.890 -10.040 75.930 -1.510 ;
        RECT 78.140 -4.920 84.840 -4.140 ;
        RECT 78.140 -7.700 78.570 -4.920 ;
        RECT 79.770 -7.140 80.190 -4.920 ;
        RECT 81.290 -7.140 81.710 -4.920 ;
        RECT 79.770 -7.640 80.200 -7.140 ;
        RECT 81.290 -7.640 81.720 -7.140 ;
        RECT 82.880 -7.150 83.300 -4.920 ;
        RECT 84.420 -7.150 84.840 -4.920 ;
        RECT 82.880 -7.650 83.310 -7.150 ;
        RECT 84.420 -7.650 84.850 -7.150 ;
        RECT 99.660 -10.040 101.700 -1.470 ;
        RECT 103.980 -4.940 110.680 -4.160 ;
        RECT 103.980 -7.720 104.410 -4.940 ;
        RECT 105.610 -7.160 106.030 -4.940 ;
        RECT 107.130 -7.160 107.550 -4.940 ;
        RECT 105.610 -7.660 106.040 -7.160 ;
        RECT 107.130 -7.660 107.560 -7.160 ;
        RECT 108.720 -7.170 109.140 -4.940 ;
        RECT 110.260 -7.170 110.680 -4.940 ;
        RECT 108.720 -7.670 109.150 -7.170 ;
        RECT 110.260 -7.670 110.690 -7.170 ;
        RECT 120.800 -10.040 122.840 -1.380 ;
        RECT 125.000 -4.940 131.700 -4.160 ;
        RECT 125.000 -7.720 125.430 -4.940 ;
        RECT 126.630 -7.160 127.050 -4.940 ;
        RECT 128.150 -7.160 128.570 -4.940 ;
        RECT 126.630 -7.660 127.060 -7.160 ;
        RECT 128.150 -7.660 128.580 -7.160 ;
        RECT 129.740 -7.170 130.160 -4.940 ;
        RECT 131.280 -7.170 131.700 -4.940 ;
        RECT 129.740 -7.670 130.170 -7.170 ;
        RECT 131.280 -7.670 131.710 -7.170 ;
        RECT 144.760 -10.040 146.800 -1.450 ;
        RECT 149.070 -4.970 155.770 -4.190 ;
        RECT 149.070 -7.750 149.500 -4.970 ;
        RECT 150.700 -7.190 151.120 -4.970 ;
        RECT 152.220 -7.190 152.640 -4.970 ;
        RECT 150.700 -7.690 151.130 -7.190 ;
        RECT 152.220 -7.690 152.650 -7.190 ;
        RECT 153.810 -7.200 154.230 -4.970 ;
        RECT 155.350 -7.200 155.770 -4.970 ;
        RECT 153.810 -7.700 154.240 -7.200 ;
        RECT 155.350 -7.700 155.780 -7.200 ;
        RECT 162.890 -10.040 164.930 -1.430 ;
        RECT 167.140 -4.970 173.840 -4.190 ;
        RECT 167.140 -7.750 167.570 -4.970 ;
        RECT 168.770 -7.190 169.190 -4.970 ;
        RECT 170.290 -7.190 170.710 -4.970 ;
        RECT 168.770 -7.690 169.200 -7.190 ;
        RECT 170.290 -7.690 170.720 -7.190 ;
        RECT 171.880 -7.200 172.300 -4.970 ;
        RECT 173.420 -7.200 173.840 -4.970 ;
        RECT 171.880 -7.700 172.310 -7.200 ;
        RECT 173.420 -7.700 173.850 -7.200 ;
        RECT 178.070 -10.040 182.000 10.520 ;
        RECT 56.710 -13.660 182.000 -10.040 ;
        RECT 178.070 -46.410 182.000 -13.660 ;
        RECT 178.070 -61.780 182.000 -53.560 ;
        RECT 85.840 -76.430 88.010 -69.230 ;
        RECT 90.180 -72.630 96.880 -71.850 ;
        RECT 90.180 -75.410 90.610 -72.630 ;
        RECT 91.810 -74.850 92.230 -72.630 ;
        RECT 93.330 -74.850 93.750 -72.630 ;
        RECT 91.810 -75.350 92.240 -74.850 ;
        RECT 93.330 -75.350 93.760 -74.850 ;
        RECT 94.920 -74.860 95.340 -72.630 ;
        RECT 96.460 -74.860 96.880 -72.630 ;
        RECT 94.920 -75.360 95.350 -74.860 ;
        RECT 96.460 -75.360 96.890 -74.860 ;
        RECT 102.370 -76.430 104.540 -69.210 ;
        RECT 106.570 -72.630 113.270 -71.850 ;
        RECT 106.570 -75.410 107.000 -72.630 ;
        RECT 108.200 -74.850 108.620 -72.630 ;
        RECT 109.720 -74.850 110.140 -72.630 ;
        RECT 108.200 -75.350 108.630 -74.850 ;
        RECT 109.720 -75.350 110.150 -74.850 ;
        RECT 111.310 -74.860 111.730 -72.630 ;
        RECT 112.850 -74.860 113.270 -72.630 ;
        RECT 111.310 -75.360 111.740 -74.860 ;
        RECT 112.850 -75.360 113.280 -74.860 ;
        RECT 118.440 -76.430 120.610 -69.140 ;
        RECT 135.020 -70.520 137.490 -68.850 ;
        RECT 178.050 -69.510 182.010 -61.780 ;
        RECT 122.530 -72.630 129.230 -71.850 ;
        RECT 122.530 -75.410 122.960 -72.630 ;
        RECT 124.160 -74.850 124.580 -72.630 ;
        RECT 125.680 -74.850 126.100 -72.630 ;
        RECT 124.160 -75.350 124.590 -74.850 ;
        RECT 125.680 -75.350 126.110 -74.850 ;
        RECT 127.270 -74.860 127.690 -72.630 ;
        RECT 128.810 -74.860 129.230 -72.630 ;
        RECT 127.270 -75.360 127.700 -74.860 ;
        RECT 128.810 -75.360 129.240 -74.860 ;
        RECT 135.180 -76.430 137.350 -70.520 ;
        RECT 139.520 -72.630 146.220 -71.850 ;
        RECT 139.520 -75.410 139.950 -72.630 ;
        RECT 141.150 -74.850 141.570 -72.630 ;
        RECT 142.670 -74.850 143.090 -72.630 ;
        RECT 141.150 -75.350 141.580 -74.850 ;
        RECT 142.670 -75.350 143.100 -74.850 ;
        RECT 144.260 -74.860 144.680 -72.630 ;
        RECT 145.800 -74.860 146.220 -72.630 ;
        RECT 144.260 -75.360 144.690 -74.860 ;
        RECT 145.800 -75.360 146.230 -74.860 ;
        RECT 178.070 -76.430 182.000 -69.510 ;
        RECT 85.480 -80.550 182.000 -76.430 ;
        RECT 178.070 -80.610 182.000 -80.550 ;

      LAYER met3 ;
        RECT 53 -124 201 69 ;
  END
END CurrentSteering_3bit_rev3
END LIBRARY

